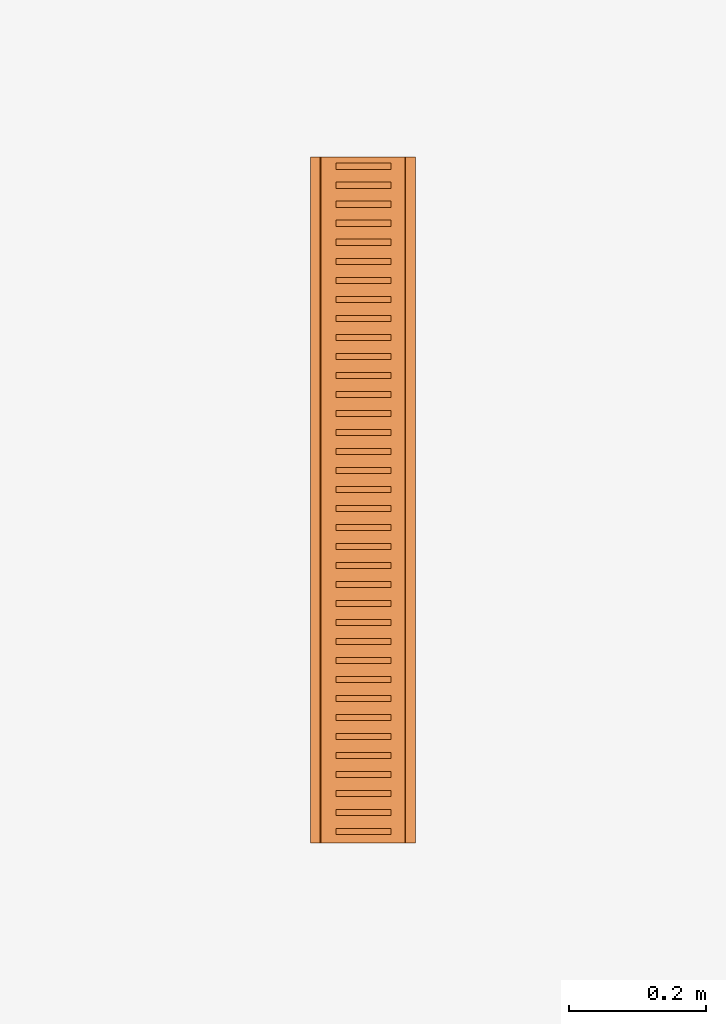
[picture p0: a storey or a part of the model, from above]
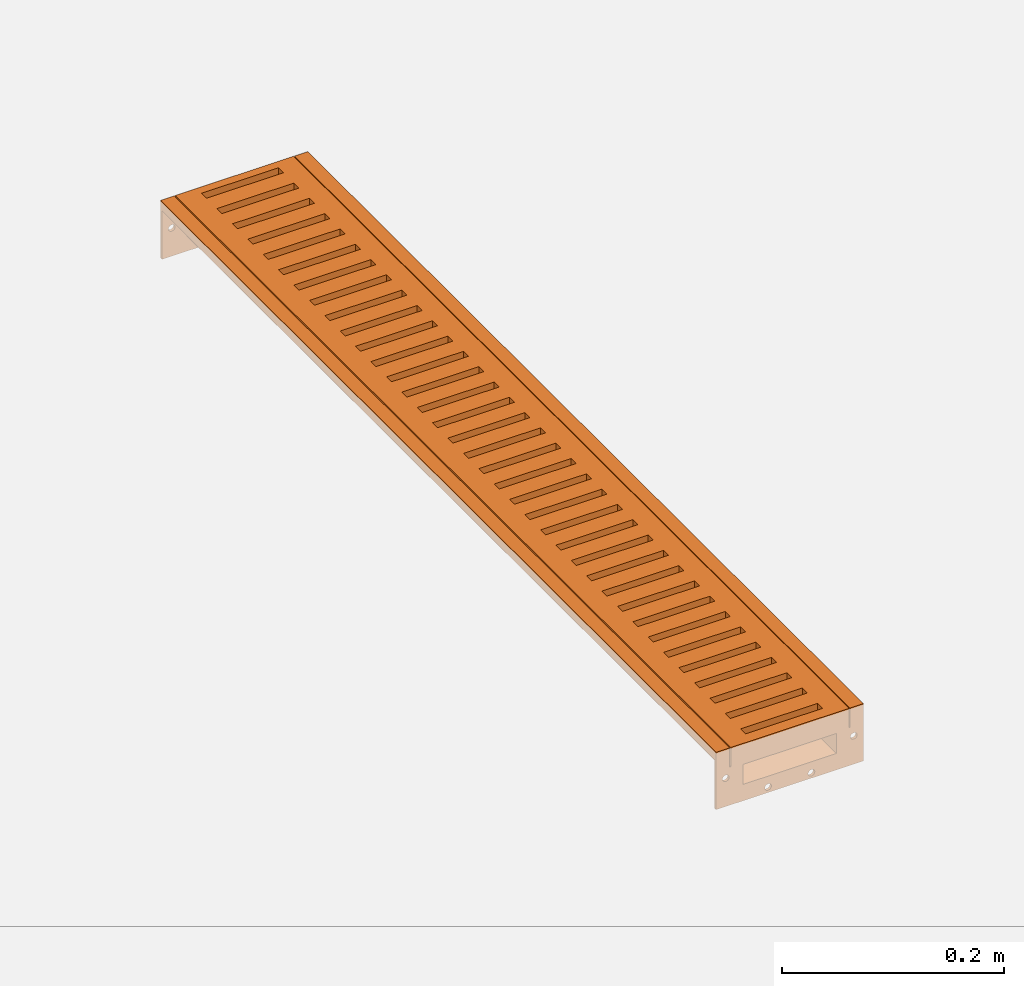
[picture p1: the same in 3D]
Properties of the parts of a building model (IFC2X3)

# File
Description: ViewDefinition [CoordinationView]
File name: 105255 - Level Invert channel-1000mm LG.ifc
Time: 2014-03-20T14:45:25
Written by: Autodesk Revit 2013
Made in: 20120221_2030(x64)

# IfcProject, Project Number
LongName: Project Name; Phase: Project Status

# IfcSite, Default
RefLatitude: 42, 21, 30, 344238; RefLongitude: -71, -3, -35, -194702; RefElevation: 0 mm

# IfcBuilding
Pset_BuildingCommon - NumberOfStoreys: 1
Other - Project Name: Project Name; Project Issue Date: Issue Date; Project Number: Project Number; Project Address: ## Street City, State Zip; Project Status: Project Status; Client Name: Owner

# IfcBuildingStorey, Level 1
LongName: Level 1; Elevation: 0 mm
Constraints - Elevation Base: 0; Elevation: 0 mm
Graphics - Line Weight: 1; Symbol: M_Level Head - Circle: M_Level Head - Circle; Symbol at End 2 Default: yes; Line Pattern: Center; Symbol at End 1 Default: no; Color: 0
Dimensions - Computation Height: 0 mm
Identity Data - Structural: no; Building Story: yes; Name: Level 1

# IfcBuildingElementProxy: 105255 - Level Invert channel-1000mm LG, ACO BD Deckline 125 Straight Channel:105255 - Level Invert channel-1000mm LG:105255 - Level Invert channel-1000mm LG:225886
In: Level 1
Material: Steel, Galvanized
Construction - 10735 - Composite Grating (White) - 500mm Long: no; 105251 - Endplate - Invert 2: no; 105525 - C250 Slotted Grating - 1000mm Long: no; 105522 - A15 Slotted Grating - 500mm Long: no; 105508 - C250 Perforated Grating - 500mm Long: no; 105523 - A15 Slotted Grating - 1000mm Long: no; 105509 - C250 Perforated Grating - 1000mm Long: no; 105251 - Endplate - Invert 1: no; 15704 - Composite Grating (Black) - 500mm Long: no; 105524 - C250 Slotted Grating - 500mm Long: no; Grating: yes; Standard Channel: yes; Non Standard Channel: no
Constraints - Level: Level: Level 1; Moves With Nearby Elements: no
Dimensions - Volume: 2814652 mm3; EndCap Distance: 1000 mm; Custom Void: 2000 mm; Custom Channel: 494 mm; Void Length: -1000 mm; Length: 500 mm; Channel Len: 994 mm
Phasing - Phase Created: New Construction
Pset_BuildingElementProxyCommon - Reference: 105255 - Level Invert channel-1000mm LG
Identity Data - Manufacturer: ACO Building Drainage; Website: www.acobd.com; Address: ACO Business Centre, Caxton Road, Bedford, MK41 0LF; Watermarked With: BIM Manager Premium Suite; Watermark1: This file is the property of ACO Technologies PLC; E-mail Technical: abdtechnical@aco.co.uk; E-mail Sales: abdcommercial@aco.co.uk; Fax: +44 (0)1462 851490; Watermarked By: www.aco.co.uk; Watermark2: This file is water marked and users are prohibited to reproduce, adapt, distribute this information; Telephone: +44 (0)1462 816666
Model Properties - Grating Product Code 10735: Load Class C250 - Composite White - 500mm long - 1.2kg; Grating Product Code 15704: Load Class C250 - Composite Black - 500mm long - 1.2kg; Grating Product Code 105525: Load Class C250 - Slotted Galvanised Steel - 500mm long - 2.3kg; Grating Product Code 105509: Load Class C250 - Perforated Galvanised Steel - 500mm long - 2.3kg; Grating Product Code 105522: Load Class A15 - Slotted Galvanised Steel - 1000mm long - 2.0kg; Grating Product Code 105523: Load Class A15 - Slotted Galvanised Steel - 500mm long - 1.0kg; Grating Product Code 105524: Load Class C250 - Slotted Galvanised Steel - 1000mm long - 4.7kg; Grating Product Code 105508: Load Class C250 - Perforated Galvanised Steel - 1000mm long - 4.8kg
General - Product Code: 105255; Seal Recycled Material Content: 0%; Maintenance guidelines: X:\Electronic Literature\Building Drainage Literature\Deckline\Deckline 125.PDF; Load Class: A15 - C250; Channel Colour: Galvanised; Seal Colour: Black; Price: POA - contact ACO; NBS Specification: NBS Section Q10 Kerbs/edgings/channels/paving accessories, Clause 180 Drainage Channel Systems; Product Description: ACO Deckline Level Invert Channel (1000 Long); Installation guidelines: X:\Electronic Literature\Building Drainage Literature\Deckline\Deckline 125.PDF; Product Range: ACO Deckline 125; Product Standard: BS EN 1433:2002 CE marked; Product Type: shallow invert surface water drainage system; Channel Recycled Material Content: 25 - 30 %; Channel Recyclable: Fully recyclable; Channel Material: Hot Dipped Galvanised Steel; Weight (Kg): 3.9; Dimensions (LxWxH): 1000 x 153 x 63; Seal Recyclable: Fully recyclable; Seal Material: Neoprene

# IfcOpeningElement: Recess
In: Level 1
Phasing - Phase Created: New Construction
Dimensions - Volume: 6390362536 mm3; Thickness: 400 mm; Perimeter: 16000 mm; Area: 16000000 mm2
Structural - Structural: no; Enable Analytical Model: no
Constraints - Related to Mass: no; Height Offset From Level: 0 mm; Level: Level: Level 1; Room Bounding: yes
Analytical Properties - Absorptance: 0.1; Thermal Resistance (R): 0.382409; Heat Transfer Coefficient (U): 2.615; Roughness: 1; Thermal mass: 604440
Construction - Function: 0; Default Thickness: 400 mm
Materials and Finishes - Structural Material: Concrete, Broom Finish
Graphics - Coarse Scale Fill Color: 0

# IfcSlab: Floor:Generic Floor - 400mm, Floor:Generic Floor - 400mm:193825
In: Level 1
PredefinedType: FLOOR; Material: Concrete, Broom Finish 400 mm
Phasing - Phase Created: New Construction
Dimensions - Volume: 6390362536 mm3; Thickness: 400 mm; Perimeter: 16000 mm; Area: 16000000 mm2
Structural - Structural: no; Enable Analytical Model: no
Constraints - Related to Mass: no; Height Offset From Level: 0 mm; Level: Level: Level 1; Room Bounding: yes
Pset_SlabCommon - Reference: Generic Floor - 400mm; IsExternal: no; LoadBearing: yes
Analytical Properties - Absorptance: 0.1; Thermal Resistance (R): 0.382409; Heat Transfer Coefficient (U): 2.615; Roughness: 1; Thermal mass: 604440
Construction - Function: 0; Default Thickness: 400 mm
Materials and Finishes - Structural Material: Concrete, Broom Finish
Graphics - Coarse Scale Fill Color: 0
